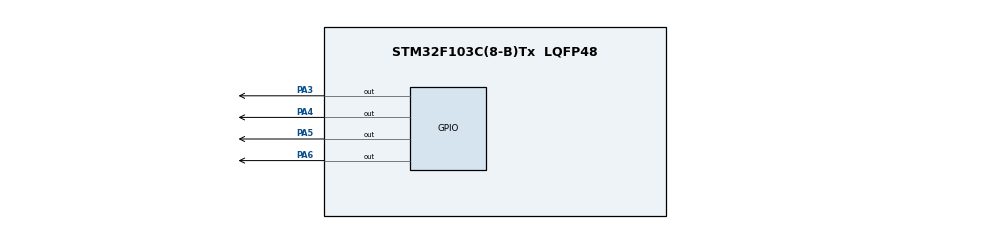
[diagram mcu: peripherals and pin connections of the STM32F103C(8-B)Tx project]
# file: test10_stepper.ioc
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Mcu.Family=STM32F1
Mcu.Name=STM32F103C(8-B)Tx
Mcu.Package=LQFP48
NVIC.PriorityGroup=NVIC_PRIORITYGROUP_4
PA3.Signal=GPIO_Output
PA4.Signal=GPIO_Output
PA5.Signal=GPIO_Output
PA6.Signal=GPIO_Output
PD0-OSC_IN.Mode=HSE-External-Oscillator
PD0-OSC_IN.Signal=RCC_OSC_IN
PD1-OSC_OUT.Mode=HSE-External-Oscillator
PD1-OSC_OUT.Signal=RCC_OSC_OUT
ProjectManager.HeapSize=0x200
ProjectManager.StackSize=0x400
ProjectManager.TargetToolchain=STM32CubeIDE
RCC.AHBFreq_Value=72000000
RCC.APB1CLKDivider=RCC_HCLK_DIV2
RCC.APB1Freq_Value=36000000
RCC.APB1TimFreq_Value=72000000
RCC.APB2Freq_Value=72000000
RCC.APB2TimFreq_Value=72000000
RCC.HCLKFreq_Value=72000000
RCC.PLLMUL=RCC_PLL_MUL9
RCC.PLLSourceVirtual=RCC_PLLSOURCE_HSE
RCC.SYSCLKFreq_VALUE=72000000
RCC.SYSCLKSource=RCC_SYSCLKSOURCE_PLLCLK
RCC.USBFreq_Value=72000000
board=custom

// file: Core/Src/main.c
/* USER CODE BEGIN Header */
/**
  ******************************************************************************
  * @file           : main.c
  * @brief          : Main program body
  ******************************************************************************
  * @attention
  *
  * Copyright (c) 2023 STMicroelectronics.
  * All rights reserved.
  *
  * This software is licensed under terms that can be found in the LICENSE file
  * in the root directory of this software component.
  * If no LICENSE file comes with this software, it is provided AS-IS.
  *
  ******************************************************************************
  */
/* USER CODE END Header */
#include "main.h"

void SystemClock_Config(void);
static void MX_GPIO_Init(void);

/* USER CODE BEGIN 0 */
#define IN1_PIN GPIO_PIN_3
#define IN1_PORT GPIOA
#define IN2_PIN GPIO_PIN_4
#define IN2_PORT GPIOA
#define IN3_PIN GPIO_PIN_5
#define IN3_PORT GPIOA
#define IN4_PIN GPIO_PIN_6
#define IN4_PORT GPIOA

void stepCCV (int steps, uint16_t delay) // CCV - Counter Clockwise
{
    for(int x=0; x<steps; x=x+1)
    {
    	   // Only Coil 4 is ON
		   HAL_GPIO_WritePin(IN1_PORT, IN1_PIN, GPIO_PIN_RESET); // IN1
		   HAL_GPIO_WritePin(IN2_PORT, IN2_PIN, GPIO_PIN_RESET); // IN2
		   HAL_GPIO_WritePin(IN3_PORT, IN3_PIN, GPIO_PIN_RESET);   // IN3
		   HAL_GPIO_WritePin(IN4_PORT, IN4_PIN, GPIO_PIN_SET);   // IN4
		   HAL_Delay(delay);
		   // Coil 3 & Coil 4 is ON
		   HAL_GPIO_WritePin(IN1_PORT, IN1_PIN, GPIO_PIN_RESET); // IN1
		   HAL_GPIO_WritePin(IN2_PORT, IN2_PIN, GPIO_PIN_RESET); // IN2
		   HAL_GPIO_WritePin(IN3_PORT, IN3_PIN, GPIO_PIN_SET);   // IN3
		   HAL_GPIO_WritePin(IN4_PORT, IN4_PIN, GPIO_PIN_SET); // IN4
		   HAL_Delay(delay);
		   // Only Coil 3 is ON
		   HAL_GPIO_WritePin(IN1_PORT, IN1_PIN, GPIO_PIN_RESET); // IN1
		   HAL_GPIO_WritePin(IN2_PORT, IN2_PIN, GPIO_PIN_RESET); // IN2
		   HAL_GPIO_WritePin(IN3_PORT, IN3_PIN, GPIO_PIN_SET); // IN3
		   HAL_GPIO_WritePin(IN4_PORT, IN4_PIN, GPIO_PIN_RESET);   // IN4
		   HAL_Delay(delay);
		   // Coil 2 & Coil 3 is ON
		   HAL_GPIO_WritePin(IN1_PORT, IN1_PIN, GPIO_PIN_RESET); // IN1
		   HAL_GPIO_WritePin(IN2_PORT, IN2_PIN, GPIO_PIN_SET); // IN2
		   HAL_GPIO_WritePin(IN3_PORT, IN3_PIN, GPIO_PIN_SET);   // IN3
		   HAL_GPIO_WritePin(IN4_PORT, IN4_PIN, GPIO_PIN_RESET);   // IN4
		   HAL_Delay(delay);
		   // Only Coil 2 is ON
		   HAL_GPIO_WritePin(IN1_PORT, IN1_PIN, GPIO_PIN_RESET); // IN1
		   HAL_GPIO_WritePin(IN2_PORT, IN2_PIN, GPIO_PIN_SET); // IN2
		   HAL_GPIO_WritePin(IN3_PORT, IN3_PIN, GPIO_PIN_RESET);   // IN3
		   HAL_GPIO_WritePin(IN4_PORT, IN4_PIN, GPIO_PIN_RESET); // IN4
		   HAL_Delay(delay);
		   // Coil 1 & Coil 2 is ON
		   HAL_GPIO_WritePin(IN1_PORT, IN1_PIN, GPIO_PIN_SET);   // IN1
		   HAL_GPIO_WritePin(IN2_PORT, IN2_PIN, GPIO_PIN_SET); // IN2
		   HAL_GPIO_WritePin(IN3_PORT, IN3_PIN, GPIO_PIN_RESET); // IN3
		   HAL_GPIO_WritePin(IN4_PORT, IN4_PIN, GPIO_PIN_RESET);   // IN4
		   HAL_Delay(delay);
		   // Only Coil 1 is ON
		   HAL_GPIO_WritePin(IN1_PORT, IN1_PIN, GPIO_PIN_SET);   // IN1
		   HAL_GPIO_WritePin(IN2_PORT, IN2_PIN, GPIO_PIN_RESET); // IN2
		   HAL_GPIO_WritePin(IN3_PORT, IN3_PIN, GPIO_PIN_RESET); // IN3
		   HAL_GPIO_WritePin(IN4_PORT, IN4_PIN, GPIO_PIN_RESET);   // IN4
		   HAL_Delay(delay);
		   // Coil 1 & Coil 4 is ON
		   HAL_GPIO_WritePin(IN1_PORT, IN1_PIN, GPIO_PIN_SET); // IN1
		   HAL_GPIO_WritePin(IN2_PORT, IN2_PIN, GPIO_PIN_RESET); // IN2
		   HAL_GPIO_WritePin(IN3_PORT, IN3_PIN, GPIO_PIN_RESET); // IN3
		   HAL_GPIO_WritePin(IN4_PORT, IN4_PIN, GPIO_PIN_SET);   // IN4
		   HAL_Delay(delay);
    }
}

void stepCV (int steps, uint16_t delay) // CV - Clockwise
{
    for(int x=0; x<steps; x=x+1)
    {
         HAL_GPIO_WritePin(IN1_PORT, IN1_PIN, GPIO_PIN_SET); // IN1
         HAL_GPIO_WritePin(IN2_PORT, IN2_PIN, GPIO_PIN_RESET); // IN2
         HAL_GPIO_WritePin(IN3_PORT, IN3_PIN, GPIO_PIN_RESET);   // IN3
         HAL_GPIO_WritePin(IN4_PORT, IN4_PIN, GPIO_PIN_RESET);   // IN4
         HAL_Delay(delay);
         // Coil 1 & Coil 2 is ON
         HAL_GPIO_WritePin(IN1_PORT, IN1_PIN, GPIO_PIN_SET); // IN1
         HAL_GPIO_WritePin(IN2_PORT, IN2_PIN, GPIO_PIN_SET); // IN2
         HAL_GPIO_WritePin(IN3_PORT, IN3_PIN, GPIO_PIN_RESET);   // IN3
         HAL_GPIO_WritePin(IN4_PORT, IN4_PIN, GPIO_PIN_RESET); // IN4
         // Only Coil 2 is ON
         HAL_Delay(delay);
         HAL_GPIO_WritePin(IN1_PORT, IN1_PIN, GPIO_PIN_RESET); // IN1
         HAL_GPIO_WritePin(IN2_PORT, IN2_PIN, GPIO_PIN_SET); // IN2
         HAL_GPIO_WritePin(IN3_PORT, IN3_PIN, GPIO_PIN_RESET); // IN3
         HAL_GPIO_WritePin(IN4_PORT, IN4_PIN, GPIO_PIN_RESET);   // IN4
         HAL_Delay(delay);
         // Coil 2 & Coil 3 is ON
         HAL_GPIO_WritePin(IN1_PORT, IN1_PIN, GPIO_PIN_RESET); // IN1
         HAL_GPIO_WritePin(IN2_PORT, IN2_PIN, GPIO_PIN_SET); // IN2
         HAL_GPIO_WritePin(IN3_PORT, IN3_PIN, GPIO_PIN_SET);   // IN3
         HAL_GPIO_WritePin(IN4_PORT, IN4_PIN, GPIO_PIN_RESET);   // IN4
         HAL_Delay(delay);
         // Only Coil 3 is ON
         HAL_GPIO_WritePin(IN1_PORT, IN1_PIN, GPIO_PIN_RESET); // IN1
         HAL_GPIO_WritePin(IN2_PORT, IN2_PIN, GPIO_PIN_RESET); // IN2
         HAL_GPIO_WritePin(IN3_PORT, IN3_PIN, GPIO_PIN_SET);   // IN3
         HAL_GPIO_WritePin(IN4_PORT, IN4_PIN, GPIO_PIN_RESET); // IN4
         HAL_Delay(delay);
         // Coil 2 & Coil 3 is ON
         HAL_GPIO_WritePin(IN1_PORT, IN1_PIN, GPIO_PIN_RESET);   // IN1
         HAL_GPIO_WritePin(IN2_PORT, IN2_PIN, GPIO_PIN_RESET); // IN2
         HAL_GPIO_WritePin(IN3_PORT, IN3_PIN, GPIO_PIN_SET); // IN3
         HAL_GPIO_WritePin(IN4_PORT, IN4_PIN, GPIO_PIN_SET);   // IN4
         HAL_Delay(delay);
         // Only Coil 4 is ON
         HAL_GPIO_WritePin(IN1_PORT, IN1_PIN, GPIO_PIN_RESET);   // IN1
         HAL_GPIO_WritePin(IN2_PORT, IN2_PIN, GPIO_PIN_RESET); // IN2
         HAL_GPIO_WritePin(IN3_PORT, IN3_PIN, GPIO_PIN_RESET); // IN3
         HAL_GPIO_WritePin(IN4_PORT, IN4_PIN, GPIO_PIN_SET);   // IN4
         HAL_Delay(delay);
         // Coil 1 & Coil 4 is ON
         HAL_GPIO_WritePin(IN1_PORT, IN1_PIN, GPIO_PIN_SET); // IN1
         HAL_GPIO_WritePin(IN2_PORT, IN2_PIN, GPIO_PIN_RESET); // IN2
         HAL_GPIO_WritePin(IN3_PORT, IN3_PIN, GPIO_PIN_RESET); // IN3
         HAL_GPIO_WritePin(IN4_PORT, IN4_PIN, GPIO_PIN_SET);   // IN4
         HAL_Delay(delay);

    }
}

/* USER CODE END 0 */

int main(void)
{

  /* MCU Configuration--------------------------------------------------------*/

  /* Reset of all peripherals, Initializes the Flash interface and the Systick. */
  HAL_Init();

  /* Configure the system clock */
  SystemClock_Config();

  /* Initialize all configured peripherals */
  MX_GPIO_Init();

  /* Infinite loop */
  /* USER CODE BEGIN WHILE */

  // initialization of rotor angle to zero
  HAL_GPIO_WritePin(IN1_PORT, IN1_PIN, GPIO_PIN_SET);   // IN1
  HAL_GPIO_WritePin(IN2_PORT, IN2_PIN, GPIO_PIN_RESET); // IN2
  HAL_GPIO_WritePin(IN3_PORT, IN3_PIN, GPIO_PIN_RESET); // IN3
  HAL_GPIO_WritePin(IN4_PORT, IN4_PIN, GPIO_PIN_SET);   // IN4
  HAL_Delay(500);

  while (1)
  {
	  stepCCV(280, 2);
	  HAL_Delay(100);
	  stepCV(280, 2);
	  HAL_Delay(100);

    /* USER CODE END WHILE */

  }
}

void SystemClock_Config(void)
{
  RCC_OscInitTypeDef RCC_OscInitStruct = {0};
  RCC_ClkInitTypeDef RCC_ClkInitStruct = {0};

  /** Initializes the RCC Oscillators according to the specified parameters
  * in the RCC_OscInitTypeDef structure.
  */
  RCC_OscInitStruct.OscillatorType = RCC_OSCILLATORTYPE_HSI;
  RCC_OscInitStruct.HSIState = RCC_HSI_ON;
  RCC_OscInitStruct.HSICalibrationValue = RCC_HSICALIBRATION_DEFAULT;
  RCC_OscInitStruct.PLL.PLLState = RCC_PLL_ON;
  RCC_OscInitStruct.PLL.PLLSource = RCC_PLLSOURCE_HSI_DIV2;
  RCC_OscInitStruct.PLL.PLLMUL = RCC_PLL_MUL9;
  if (HAL_RCC_OscConfig(&RCC_OscInitStruct) != HAL_OK)
  {
    Error_Handler();
  }

  /** Initializes the CPU, AHB and APB buses clocks
  */
  RCC_ClkInitStruct.ClockType = RCC_CLOCKTYPE_HCLK|RCC_CLOCKTYPE_SYSCLK
                              |RCC_CLOCKTYPE_PCLK1|RCC_CLOCKTYPE_PCLK2;
  RCC_ClkInitStruct.SYSCLKSource = RCC_SYSCLKSOURCE_PLLCLK;
  RCC_ClkInitStruct.AHBCLKDivider = RCC_SYSCLK_DIV1;
  RCC_ClkInitStruct.APB1CLKDivider = RCC_HCLK_DIV2;
  RCC_ClkInitStruct.APB2CLKDivider = RCC_HCLK_DIV1;

  if (HAL_RCC_ClockConfig(&RCC_ClkInitStruct, FLASH_LATENCY_1) != HAL_OK)
  {
    Error_Handler();
  }
}

static void MX_GPIO_Init(void)
{
  GPIO_InitTypeDef GPIO_InitStruct = {0};

  /* GPIO Ports Clock Enable */
  __HAL_RCC_GPIOD_CLK_ENABLE();
  __HAL_RCC_GPIOA_CLK_ENABLE();

  /*Configure GPIO pin Output Level */
  HAL_GPIO_WritePin(GPIOA, GPIO_PIN_3|GPIO_PIN_4|GPIO_PIN_5|GPIO_PIN_6, GPIO_PIN_RESET);

  /*Configure GPIO pins : PA3 PA4 PA5 PA6 */
  GPIO_InitStruct.Pin = GPIO_PIN_3|GPIO_PIN_4|GPIO_PIN_5|GPIO_PIN_6;
  GPIO_InitStruct.Mode = GPIO_MODE_OUTPUT_PP;
  GPIO_InitStruct.Pull = GPIO_NOPULL;
  GPIO_InitStruct.Speed = GPIO_SPEED_FREQ_LOW;
  HAL_GPIO_Init(GPIOA, &GPIO_InitStruct);

}

void Error_Handler(void)
{
  __disable_irq();
  while (1)
  {
  }
}
